VERSION 5.7 ;
  NOWIREEXTENSIONATPIN ON ;
  DIVIDERCHAR "/" ;
  BUSBITCHARS "[]" ;
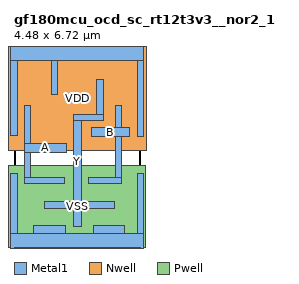
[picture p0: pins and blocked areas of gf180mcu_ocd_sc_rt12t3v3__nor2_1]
MACRO gf180mcu_ocd_sc_rt12t3v3__nor2_1
  CLASS CORE ;
  FOREIGN gf180mcu_ocd_sc_rt12t3v3__nor2_1 ;
  ORIGIN 0.000 0.000 ;
  SIZE 4.480 BY 6.720 ;
  SYMMETRY X Y ;
  SITE unithd ;
  PIN A
    DIRECTION INPUT ;
    USE SIGNAL ;
    ANTENNAGATEAREA 1.672300 ;
    PORT
      LAYER Metal1 ;
        RECT 0.370 3.490 0.600 4.825 ;
        RECT 0.370 3.160 1.870 3.490 ;
        RECT 0.370 2.285 0.600 3.160 ;
        RECT 0.370 2.055 1.800 2.285 ;
    END
  END A
  PIN B
    DIRECTION INPUT ;
    USE SIGNAL ;
    ANTENNAGATEAREA 1.672300 ;
    PORT
      LAYER Metal1 ;
        RECT 3.585 4.050 3.815 4.825 ;
        RECT 2.745 3.725 4.095 4.050 ;
        RECT 3.585 2.285 3.815 3.725 ;
        RECT 2.625 2.055 3.815 2.285 ;
    END
  END B
  PIN Y
    DIRECTION OUTPUT ;
    USE SIGNAL ;
    ANTENNADIFFAREA 1.285600 ;
    PORT
      LAYER Metal1 ;
        RECT 2.925 4.510 3.155 5.730 ;
        RECT 2.110 4.280 3.155 4.510 ;
        RECT 2.110 1.425 2.370 4.280 ;
        RECT 1.080 1.195 3.540 1.425 ;
        RECT 2.110 0.535 2.370 1.195 ;
    END
  END Y
  PIN VDD
    DIRECTION INOUT ;
    USE POWER ;
    SHAPE ABUTMENT ;
    PORT
      LAYER Nwell ;
        RECT -0.610 3.245 5.090 7.330 ;
      LAYER Metal1 ;
        RECT -0.115 6.420 4.595 7.020 ;
        RECT -0.115 3.750 0.115 6.420 ;
        RECT 1.325 5.205 1.555 6.420 ;
        RECT 4.365 3.745 4.595 6.420 ;
    END
  END VDD
  PIN VSS
    DIRECTION INOUT ;
    USE GROUND ;
    SHAPE ABUTMENT ;
    PORT
      LAYER Pwell ;
        RECT -0.180 -0.180 4.660 2.695 ;
        RECT 0.000 -0.300 4.480 -0.180 ;
      LAYER Metal1 ;
        RECT -0.115 0.300 0.115 2.410 ;
        RECT 0.700 0.300 1.810 0.585 ;
        RECT 2.820 0.300 3.900 0.585 ;
        RECT 4.365 0.300 4.595 2.410 ;
        RECT -0.115 -0.300 4.595 0.300 ;
    END
  END VSS
  OBS
      LAYER Metal1 ;
        RECT 0.525 5.290 0.755 6.190 ;
        RECT 2.125 5.960 3.955 6.190 ;
        RECT 2.125 5.290 2.355 5.960 ;
        RECT 0.525 5.060 1.060 5.290 ;
        RECT 0.830 4.975 1.060 5.060 ;
        RECT 1.785 5.060 2.355 5.290 ;
        RECT 1.785 4.975 2.015 5.060 ;
        RECT 3.725 5.055 3.955 5.960 ;
        RECT 0.830 4.745 2.015 4.975 ;
  END
END gf180mcu_ocd_sc_rt12t3v3__nor2_1
END LIBRARY

